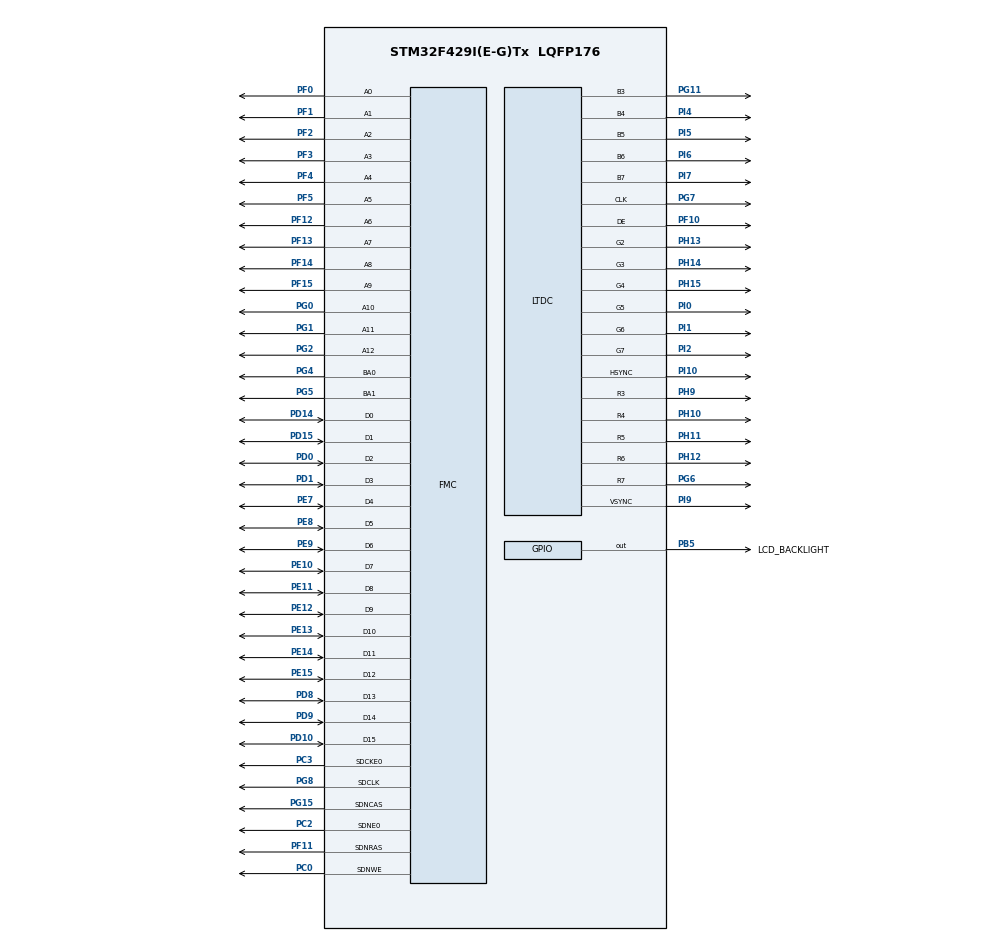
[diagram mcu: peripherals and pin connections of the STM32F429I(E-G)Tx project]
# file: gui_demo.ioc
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DMA2D.ColorMode=DMA2D_OUTPUT_RGB565
FMC.CASLatency1=FMC_SDRAM_CAS_LATENCY_2
FMC.ColumnBitsNumber1=FMC_SDRAM_COLUMN_BITS_NUM_9
FMC.ExitSelfRefreshDelay1=7
FMC.LoadToActiveDelay1=2
FMC.RCDDelay1=2
FMC.RPDelay1=2
FMC.ReadBurst1=FMC_SDRAM_RBURST_ENABLE
FMC.RowCycleDelay1=6
FMC.SelfRefreshTime1=6
FMC.WriteRecoveryTime1=4
LTDC.ActiveH=600
LTDC.ActiveW=1024
LTDC.Alpha0_L0=0
LTDC.Alpha_L0=255
LTDC.FBStartAdress_L0=3221225472
LTDC.HBP=140
LTDC.HFP=160
LTDC.HSync=20
LTDC.ImageHeight_L0=600
LTDC.ImageWidth_L0=1024
LTDC.Layers=0
LTDC.PixelFormat_L0=LTDC_PIXEL_FORMAT_RGB565
LTDC.VBP=20
LTDC.VFP=12
LTDC.VSync=3
LTDC.WindowX1_L0=1024
LTDC.WindowY1_L0=600
Mcu.Family=STM32F4
Mcu.Name=STM32F429I(E-G)Tx
Mcu.Package=LQFP176
NVIC.PriorityGroup=NVIC_PRIORITYGROUP_4
PB5.GPIO_Label=LCD_BACKLIGHT
PB5.GPIO_PuPd=GPIO_PULLUP
PB5.GPIO_Speed=GPIO_SPEED_FREQ_HIGH
PB5.PinState=GPIO_PIN_SET
PB5.Signal=GPIO_Output
PC0.Signal=FMC_SDNWE
PC2.Mode=SdramChipSelect1_1
PC2.Signal=FMC_SDNE0
PC3.Mode=SdramChipSelect1_1
PC3.Signal=FMC_SDCKE0
PD0.Signal=FMC_D2_DA2
PD1.Signal=FMC_D3_DA3
PD10.Signal=FMC_D15_DA15
PD14.Signal=FMC_D0_DA0
PD15.Signal=FMC_D1_DA1
PD8.Signal=FMC_D13_DA13
PD9.Signal=FMC_D14_DA14
PE10.Signal=FMC_D7_DA7
PE11.Signal=FMC_D8_DA8
PE12.Signal=FMC_D9_DA9
PE13.Signal=FMC_D10_DA10
PE14.Signal=FMC_D11_DA11
PE15.Signal=FMC_D12_DA12
PE7.Signal=FMC_D4_DA4
PE8.Signal=FMC_D5_DA5
PE9.Signal=FMC_D6_DA6
PF0.Signal=FMC_A0
PF1.Signal=FMC_A1
PF10.GPIO_Speed=GPIO_SPEED_FREQ_HIGH
PF10.Mode=RGB565
PF10.Signal=LTDC_DE
PF11.Signal=FMC_SDNRAS
PF12.Signal=FMC_A6
PF13.Signal=FMC_A7
PF14.Signal=FMC_A8
PF15.Signal=FMC_A9
PF2.Signal=FMC_A2
PF3.Signal=FMC_A3
PF4.Signal=FMC_A4
PF5.Signal=FMC_A5
PG0.Signal=FMC_A10
PG1.Signal=FMC_A11
PG11.GPIO_Speed=GPIO_SPEED_FREQ_HIGH
PG11.Mode=RGB565
PG11.Signal=LTDC_B3
PG15.Signal=FMC_SDNCAS
PG2.Signal=FMC_A12
PG4.Signal=FMC_A14_BA0
PG5.Signal=FMC_A15_BA1
PG6.GPIO_Mode=GPIO_MODE_AF_PP
PG6.GPIO_Speed=GPIO_SPEED_FREQ_HIGH
PG6.Mode=RGB565
PG6.Signal=LTDC_R7
PG7.GPIO_Speed=GPIO_SPEED_FREQ_HIGH
PG7.Mode=RGB565
PG7.Signal=LTDC_CLK
PG8.Signal=FMC_SDCLK
PH0/OSC_IN.Mode=HSE-External-Oscillator
PH0/OSC_IN.Signal=RCC_OSC_IN
PH1/OSC_OUT.Mode=HSE-External-Oscillator
PH1/OSC_OUT.Signal=RCC_OSC_OUT
PH10.GPIO_Speed=GPIO_SPEED_FREQ_HIGH
PH10.Mode=RGB565
PH10.Signal=LTDC_R4
PH11.GPIO_Speed=GPIO_SPEED_FREQ_HIGH
PH11.Mode=RGB565
PH11.Signal=LTDC_R5
PH12.GPIO_Speed=GPIO_SPEED_FREQ_HIGH
PH12.Mode=RGB565
PH12.Signal=LTDC_R6
PH13.GPIO_Speed=GPIO_SPEED_FREQ_HIGH
PH13.Mode=RGB565
PH13.Signal=LTDC_G2
PH14.GPIO_Speed=GPIO_SPEED_FREQ_HIGH
PH14.Mode=RGB565
PH14.Signal=LTDC_G3
PH15.GPIO_Speed=GPIO_SPEED_FREQ_HIGH
PH15.Mode=RGB565
PH15.Signal=LTDC_G4
PH9.GPIO_Speed=GPIO_SPEED_FREQ_HIGH
PH9.Mode=RGB565
PH9.Signal=LTDC_R3
PI0.GPIO_Speed=GPIO_SPEED_FREQ_HIGH
PI0.Mode=RGB565
PI0.Signal=LTDC_G5
PI1.GPIO_Speed=GPIO_SPEED_FREQ_HIGH
PI1.Mode=RGB565
PI1.Signal=LTDC_G6
PI10.GPIO_Speed=GPIO_SPEED_FREQ_HIGH
PI10.Mode=RGB565
PI10.Signal=LTDC_HSYNC
PI2.GPIO_Speed=GPIO_SPEED_FREQ_HIGH
PI2.Mode=RGB565
PI2.Signal=LTDC_G7
PI4.GPIO_Speed=GPIO_SPEED_FREQ_HIGH
PI4.Mode=RGB565
PI4.Signal=LTDC_B4
PI5.GPIO_Speed=GPIO_SPEED_FREQ_HIGH
PI5.Mode=RGB565
PI5.Signal=LTDC_B5
PI6.GPIO_Speed=GPIO_SPEED_FREQ_HIGH
PI6.Mode=RGB565
PI6.Signal=LTDC_B6
PI7.GPIO_Speed=GPIO_SPEED_FREQ_HIGH
PI7.Mode=RGB565
PI7.Signal=LTDC_B7
PI9.GPIO_Speed=GPIO_SPEED_FREQ_HIGH
PI9.Mode=RGB565
PI9.Signal=LTDC_VSYNC
ProjectManager.HeapSize=0x200
ProjectManager.StackSize=0x400
ProjectManager.TargetToolchain=STM32CubeIDE
RCC.48MHZClocksFreq_Value=45000000
RCC.AHBFreq_Value=25000000
RCC.APB1CLKDivider=RCC_HCLK_DIV4
RCC.APB1Freq_Value=6250000
RCC.APB1TimFreq_Value=12500000
RCC.APB2CLKDivider=RCC_HCLK_DIV2
RCC.APB2Freq_Value=12500000
RCC.APB2TimFreq_Value=25000000
RCC.CortexFreq_Value=25000000
RCC.HCLKFreq_Value=25000000
RCC.HSE_VALUE=25000000
RCC.HSI_VALUE=16000000
RCC.LSE_VALUE=32768
RCC.PLLM=25
RCC.PLLN=180
RCC.PLLSAIDivR=RCC_PLLSAIDIVR_4
RCC.PLLSAIN=360
RCC.PLLSourceVirtual=RCC_PLLSOURCE_HSE
RCC.PWREXT_OverDrive=PWREXT_OverDrive_ACTIVATED
RCC.PWR_Regulator_Voltage_Scale=PWR_REGULATOR_VOLTAGE_SCALE1
RCC.SYSCLKFreq_VALUE=25000000
RCC.SYSCLKSource=RCC_SYSCLKSOURCE_HSE
RCC.VCOOutputFreq_Value=180000000
SH.FMC_A0.0=FMC_A0,13b-sda1
SH.FMC_A1.0=FMC_A1,13b-sda1
SH.FMC_A10.0=FMC_A10,13b-sda1
SH.FMC_A11.0=FMC_A11,13b-sda1
SH.FMC_A12.0=FMC_A12,13b-sda1
SH.FMC_A14_BA0.0=FMC_BA0,FourSdramBanks1
SH.FMC_A15_BA1.0=FMC_BA1,FourSdramBanks1
SH.FMC_A2.0=FMC_A2,13b-sda1
SH.FMC_A3.0=FMC_A3,13b-sda1
SH.FMC_A4.0=FMC_A4,13b-sda1
SH.FMC_A5.0=FMC_A5,13b-sda1
SH.FMC_A6.0=FMC_A6,13b-sda1
SH.FMC_A7.0=FMC_A7,13b-sda1
SH.FMC_A8.0=FMC_A8,13b-sda1
SH.FMC_A9.0=FMC_A9,13b-sda1
SH.FMC_D0_DA0.0=FMC_D0,sd-16b-d1
SH.FMC_D10_DA10.0=FMC_D10,sd-16b-d1
SH.FMC_D11_DA11.0=FMC_D11,sd-16b-d1
SH.FMC_D12_DA12.0=FMC_D12,sd-16b-d1
SH.FMC_D13_DA13.0=FMC_D13,sd-16b-d1
SH.FMC_D14_DA14.0=FMC_D14,sd-16b-d1
SH.FMC_D15_DA15.0=FMC_D15,sd-16b-d1
SH.FMC_D1_DA1.0=FMC_D1,sd-16b-d1
SH.FMC_D2_DA2.0=FMC_D2,sd-16b-d1
SH.FMC_D3_DA3.0=FMC_D3,sd-16b-d1
SH.FMC_D4_DA4.0=FMC_D4,sd-16b-d1
SH.FMC_D5_DA5.0=FMC_D5,sd-16b-d1
SH.FMC_D6_DA6.0=FMC_D6,sd-16b-d1
SH.FMC_D7_DA7.0=FMC_D7,sd-16b-d1
SH.FMC_D8_DA8.0=FMC_D8,sd-16b-d1
SH.FMC_D9_DA9.0=FMC_D9,sd-16b-d1
SH.FMC_SDCLK.0=FMC_SDCLK,13b-sda1
SH.FMC_SDNCAS.0=FMC_SDNCAS,13b-sda1
SH.FMC_SDNRAS.0=FMC_SDNRAS,13b-sda1
SH.FMC_SDNWE.0=FMC_SDNWE,13b-sda1
VP_DMA2D_VS_DMA2D.Mode=DMA2D_Activate
board=custom

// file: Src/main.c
/* USER CODE BEGIN Header */
/**
  ******************************************************************************
  * @file           : main.c
  * @brief          : Main program body
  ******************************************************************************
  * @attention
  *
  * Copyright (c) 2023 STMicroelectronics.
  * All rights reserved.
  *
  * This software is licensed under terms that can be found in the LICENSE file
  * in the root directory of this software component.
  * If no LICENSE file comes with this software, it is provided AS-IS.
  *
  ******************************************************************************
  */
/* USER CODE END Header */
#include "main.h"
#include "ltdc.h"
#include "gpio.h"
#include "fmc.h"
#include "touchpad/touchpad.h"

/* USER CODE BEGIN Includes */
#include "lvgl/lvgl.h"
#include "lv_demos/src/lv_demo_widgets/lv_demo_widgets.h"
#include "lv_demos/src/lv_demo_music/lv_demo_music.h"
#include "lvgl_dirver/timer.h"
#include "lvgl_dirver/lv_port_disp.h"
#include "lvgl_dirver/lv_port_indev.h"
/* USER CODE END Includes */

void SystemClock_Config(void);

/* USER CODE BEGIN 0 */
void FillRect(uint16_t x, uint16_t y, uint16_t w, uint16_t h, uint16_t color)
{
	void* pDist = &(((uint16_t*)ATK_RGBLCD_LTDC_LAYER_FB_ADDR)[y*1024 + x]);
	DMA2D_Fill(pDist, w, h, 1024 - w, LTDC_PIXEL_FORMAT_RGB565, color);
}
/* USER CODE END 0 */

int main(void)
{

  /* MCU Configuration--------------------------------------------------------*/

  /* Reset of all peripherals, Initializes the Flash interface and the Systick. */
  HAL_Init();

  /* Configure the system clock */
  SystemClock_Config();

  /* Initialize all configured peripherals */
  MX_GPIO_Init();
  MX_LTDC_Init();
  MX_FMC_Init();
  TIM3_Init(999,89);							//定时器初始化(1ms中断),用于给lvgl提供心跳节拍
  /* USER CODE BEGIN 2 */

  /*开启屏幕背光*/
  HAL_GPIO_WritePin(LCD_BACKLIGHT_GPIO_Port, LCD_BACKLIGHT_Pin, GPIO_PIN_SET);
  tp_dev.init();
  /*清屏*/
  //FillRect(0, 0, 1024, 600, 0xFFFF);

  /* 绘制数据条*/
  //FillRect(380, 240, 40, 220,0x0f00);
  //FillRect(460, 200, 40, 260,0x0ef1);
  //FillRect(540, 160, 40, 300,0xf800);
  //FillRect(620, 120, 40, 340,0x001f);

  /*绘制X轴*/
  //FillRect(340,  460, 360, 1,    0x0000);
  lv_init();
  lv_port_disp_init();
  lv_port_indev_init();
  //lv_demo_widgets();
  lv_demo_music();
  /* USER CODE END 2 */

  /* Infinite loop */
  /* USER CODE BEGIN WHILE */
  while (1)
  {
      tp_dev.scan(0);
      lv_task_handler();
      HAL_Delay(3);
    /* USER CODE END WHILE */

  }
}

void SystemClock_Config(void)
{
  RCC_OscInitTypeDef RCC_OscInitStruct = {0};
  RCC_ClkInitTypeDef RCC_ClkInitStruct = {0};

  /** Configure the main internal regulator output voltage
  */
  __HAL_RCC_PWR_CLK_ENABLE();
  __HAL_PWR_VOLTAGESCALING_CONFIG(PWR_REGULATOR_VOLTAGE_SCALE1);

  /** Initializes the RCC Oscillators according to the specified parameters
  * in the RCC_OscInitTypeDef structure.
  */
  RCC_OscInitStruct.OscillatorType = RCC_OSCILLATORTYPE_HSE;
  RCC_OscInitStruct.HSEState = RCC_HSE_ON;
  RCC_OscInitStruct.PLL.PLLState = RCC_PLL_ON;
  RCC_OscInitStruct.PLL.PLLSource = RCC_PLLSOURCE_HSE;
  RCC_OscInitStruct.PLL.PLLN = 360;
  RCC_OscInitStruct.PLL.PLLM = 25;
  RCC_OscInitStruct.PLL.PLLP = 2;
  RCC_OscInitStruct.PLL.PLLQ = 8;
  if (HAL_RCC_OscConfig(&RCC_OscInitStruct) != HAL_OK)
  {
    Error_Handler();
  }

  /** Activate the Over-Drive mode
  */
  if (HAL_PWREx_EnableOverDrive() != HAL_OK)
  {
    Error_Handler();
  }

  /** Initializes the CPU, AHB and APB buses clocks
  */
  RCC_ClkInitStruct.ClockType = RCC_CLOCKTYPE_HCLK|RCC_CLOCKTYPE_SYSCLK
                              |RCC_CLOCKTYPE_PCLK1|RCC_CLOCKTYPE_PCLK2;
  RCC_ClkInitStruct.SYSCLKSource = RCC_SYSCLKSOURCE_PLLCLK;
  RCC_ClkInitStruct.AHBCLKDivider = RCC_SYSCLK_DIV1;
  RCC_ClkInitStruct.APB1CLKDivider = RCC_HCLK_DIV4;
  RCC_ClkInitStruct.APB2CLKDivider = RCC_HCLK_DIV2;

  if (HAL_RCC_ClockConfig(&RCC_ClkInitStruct, FLASH_LATENCY_5) != HAL_OK)
  {
    Error_Handler();
  }

  HAL_SYSTICK_CLKSourceConfig(SYSTICK_CLKSOURCE_HCLK);
}

void Error_Handler(void)
{
  __disable_irq();
  while (1)
  {
  }
}
